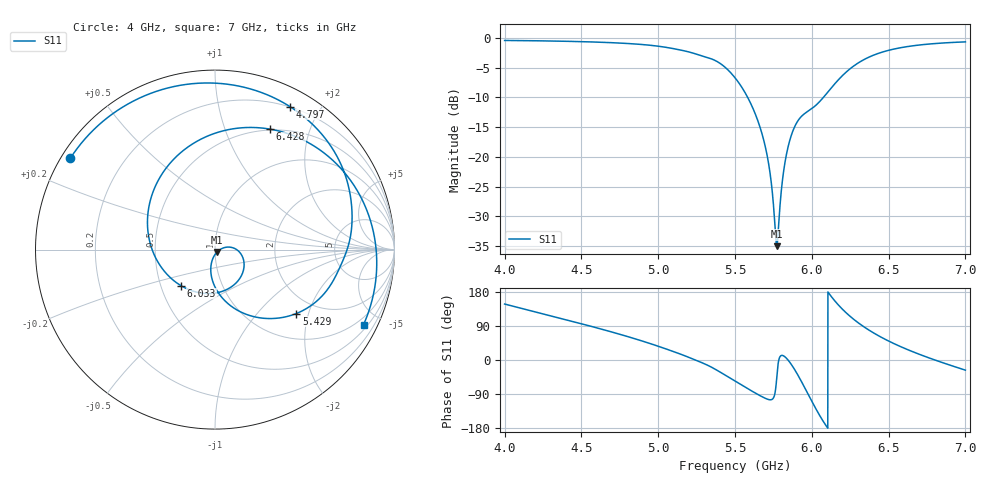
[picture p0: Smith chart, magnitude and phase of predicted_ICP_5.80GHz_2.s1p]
! ICP-predicted S11, target max centred GHz at -10 dB. Complex ensemble mean (passive and causal);
! its |S11| can differ slightly from the dB-domain mean reported in designs.csv.
!  Air_gap = 3.1mm
!  W_Patch = 22.38mm
!  L_Patch = 16.45mm
!  Sx = 4.79mm
!  Sy = 4.52mm
!  W_Patch1 = 15.15mm
!  WS = 0.43mm
!  Curve_Amp1 = 2.12mm
!  Extra = 3.08mm
# GHz S MA R 50
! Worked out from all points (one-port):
!   3001 points, 4 GHz to 7 GHz, reference 50 ohm
!   lowest |S11| = -35.0 dB at 5.772 GHz (marker M1), VSWR 1.04, Z = 51.3 - j1.29 ohm
!   |S11| at or under -10 dB: 5.583 GHz to 6.075 GHz (492.9 MHz wide, 8.46 % of centre)
!   S11 on the Smith chart (normalised r, x): 4 GHz: 0.03, +0.29; 4.797 GHz: 0.20, +1.64; 5.429 GHz: 1.57, -1.67; 6.033 GHz: 0.63, -0.28; 6.428 GHz: 0.49, +1.44; 7 GHz: 0.69, -4.09
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4  0.9532 147.7
4.375  0.9395 108.9
4.567  0.9262 88.5
4.75  0.9064 67.9
4.797  0.8994 62.3
4.98  0.8593 39.0
5.125  0.8016 18.5
5.307  0.6926 -11.0
5.429  0.5765 -38.1
5.5  0.4628 -55.6
5.604  0.2782 -80.7
5.682  0.1463 -98.1
5.726  0.07644 -104.9
5.762  0.02412 -83.8
5.772  0.01772 -45.1
5.782  0.02416 -6.4
5.822  0.08441 9.4
5.875  0.1629 -16.7
5.918  0.2083 -46.0
5.965  0.2371 -81.6
6.033  0.2763 -133.4
6.139  0.3967 161.3
6.25  0.5517 115.1
6.336  0.6541 88.5
6.428  0.7381 65.4
6.625  0.8477 27.2
6.801  0.8977 0.1
7  0.9273 -26.8
